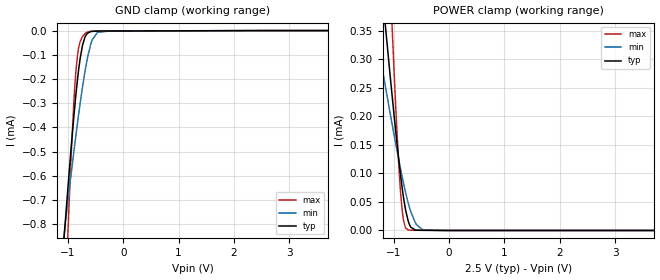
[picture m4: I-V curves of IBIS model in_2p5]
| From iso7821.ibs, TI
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|   in_2p5 Model
[Model]   in_2p5
Model_type   Input
Vinl = 0.75
Vinh = 1.75
|   typ   min   max
|   (nom PVT)   (fast PVT)   (slow PVT)
C_comp   3.281e-15   3.281e-15   3.250e-14
[Model spec]
|subparameter
Vinl   0.75   0.675   0.825
Vinh   1.75   1.575   1.925
| Where nom  PVT is Nominal Process, 2.5V, 27C
|   Fast PVT is Strong Process,  2.75V, -55C
|   Slow PVT is Weak Process,   2.25V, 150C
[Voltage Range]   2.5   2.25   2.75
|Ambient Temperature   25   125   -55
|Junction Temperature
[Temperature Range]   27   150   -55
[Power Clamp Reference]   2.5   2.25   2.75
[GND Clamp Reference]   0   0   0
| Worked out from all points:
|   GND clamp passes 1 mA (typ) near -1.12 V on its own axis
[GND Clamp]
|   Voltage   I(typ)   I(min)   I(max)
-2.5V     -5.567mA   -3.855mA   -11.2mA
-1.071V   -859.9uA   -843.3uA   -1.249mA
-1.015V   -691.9uA   -732.5uA   -914.2uA
-965mV    -547.7uA   -635.6uA   -635.6uA
-894mV    -356.2uA   -501.7uA   -297uA
-827.5mV  -201.6uA   -381.9uA   -101.5uA
-737.5mV  -61.36uA   -233.7uA   -24.74uA
-643.8mV  -10.62uA   -108.8uA   -5.86uA
-564mV    -3.337uA   -39.15uA   -2.62uA
-468.2mV  -2.078uA   -7.417uA   -2.095uA
-250mV    -1.826uA   -1.892uA   -1.932uA
5V        0A         0A         0A
[POWER Clamp]
|   Voltage   I(typ)   I(min)   I(max)
-2.5V     1.812mA    1.039mA    3.985mA
-1.351V   565.2uA    364.2uA    1.113mA
-1.196V   404.1uA    277.3uA    740.6uA
-1.053V   258.8uA    198.6uA    407.1uA
-990.2mV  197.6uA    165uA      269.2uA
-924.3mV  136.7uA    131uA      139.5uA
-874.8mV  94.88uA    106.6uA    63.72uA
-822.5mV  56.84uA    82.23uA    17.11uA
-740mV    16.82uA    48.51uA    910.2nA
-612.5mV  771.4nA    14.03uA    395.2nA
-486.3mV  326.4nA    1.63uA     313.2nA
5V        0A         0A         0A
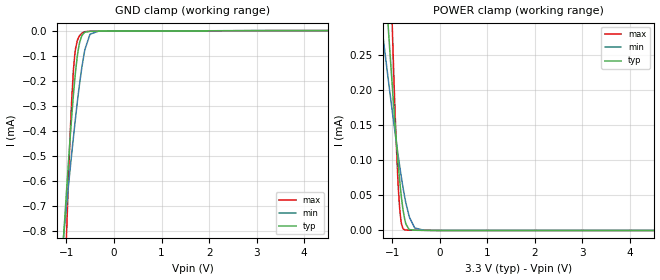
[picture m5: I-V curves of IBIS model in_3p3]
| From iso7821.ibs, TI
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|   in_3p3 Model
[Model]   in_3p3
Model_type   Input
Vinl = 0.99
Vinh = 2.31
|   typ   min   max
|   (nom PVT)   (fast PVT)   (slow PVT)
C_comp   3.281e-15   3.281e-15   3.329e-14
[Model spec]
|subparameter
Vinl   0.99   0.891   1.089
Vinh   2.31   2.079   2.541
| Where nom  PVT is Nominal Process, 3.3V, 27C
|   Fast PVT is Strong Process,  3.63V, -55C
|   Slow PVT is Weak Process,   2.97V, 150C
[Voltage Range]   3.3   2.97   3.63
|Ambient Temperature   25   125   -55
|Junction Temperature
[Temperature Range]   27   150   -55
[Power Clamp Reference]   3.3   2.97   3.63
[GND Clamp Reference]   0   0   0
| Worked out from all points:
|   GND clamp passes 1 mA (typ) near -1.12 V on its own axis
|   POWER clamp passes 1 mA (typ) near -1.76 V on its own axis
[GND Clamp]
|   Voltage   I(typ)   I(min)   I(max)
-3.3V     -8.284mA   -5.57mA    -16.97mA
-1.076V   -873.8uA   -852.4uA   -1.277mA
-1.002V   -654.6uA   -707.6uA   -841.1uA
-893.3mV  -354.6uA   -500.5uA   -294.5uA
-853.4mV  -258.1uA   -427.8uA   -159.9uA
-825mV    -196.7uA   -377.6uA   -97.46uA
-772.2mV  -104.4uA   -288.5uA   -41.12uA
-722.7mV  -47.98uA   -211.7uA   -20.38uA
-620.4mV  -7.55uA    -84.56uA   -4.818uA
-505.2mV  -2.819uA   -14.66uA   -2.744uA
-330mV    -2.413uA   -2.673uA   -2.551uA
6.6V      0A         0A         0A
[POWER Clamp]
|   Voltage   I(typ)   I(min)   I(max)
-3.3V     2.693mA    1.517mA    6.009mA
-1.242V   451.1uA    302.7uA    849uA
-1.198V   405.5uA    278.1uA    743.9uA
-1.049V   255uA      196.5uA    398.4uA
-965.9mV  174.7uA    152.3uA    218.9uA
-878.8mV  98.13uA    108.5uA    68.84uA
-842.5mV  70.44uA    91.34uA    30.66uA
-805.2mV  46.22uA    74.6uA     9.403uA
-737.2mV  15.94uA    47.51uA    852.4nA
-526mV    364.9nA    3.505uA    338.9nA
-330mV    219.3nA    268.9nA    212.6nA
6.6V      0A         0A         0A
